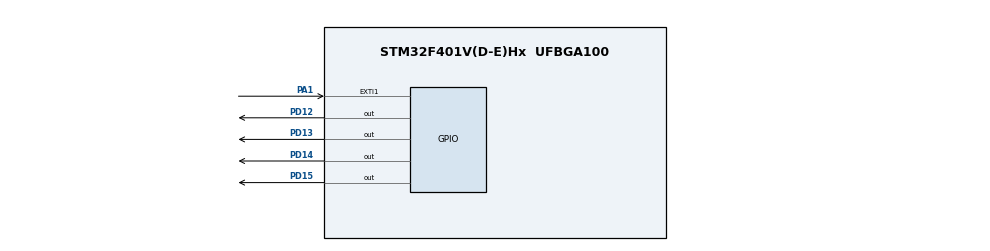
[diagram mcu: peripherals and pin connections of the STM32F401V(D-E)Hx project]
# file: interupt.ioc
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Mcu.Family=STM32F4
Mcu.Name=STM32F401V(D-E)Hx
Mcu.Package=UFBGA100
NVIC.EXTI1_IRQn=true\:0\:0\:false\:false\:true\:true\:true
NVIC.PriorityGroup=NVIC_PRIORITYGROUP_4
NVIC.TIM2_IRQn=true\:0\:0\:false\:false\:true\:true\:true
PA1.Signal=GPXTI1
PD12.GPIO_ModeDefaultOutputPP=GPIO_MODE_OUTPUT_PP
PD12.GPIO_PuPd=GPIO_NOPULL
PD12.GPIO_Speed=GPIO_SPEED_FREQ_HIGH
PD12.PinState=GPIO_PIN_RESET
PD12.Signal=GPIO_Output
PD13.GPIO_ModeDefaultOutputPP=GPIO_MODE_OUTPUT_PP
PD13.GPIO_PuPd=GPIO_NOPULL
PD13.GPIO_Speed=GPIO_SPEED_FREQ_HIGH
PD13.PinState=GPIO_PIN_RESET
PD13.Signal=GPIO_Output
PD14.GPIO_ModeDefaultOutputPP=GPIO_MODE_OUTPUT_PP
PD14.GPIO_PuPd=GPIO_NOPULL
PD14.GPIO_Speed=GPIO_SPEED_FREQ_HIGH
PD14.PinState=GPIO_PIN_RESET
PD14.Signal=GPIO_Output
PD15.GPIO_ModeDefaultOutputPP=GPIO_MODE_OUTPUT_PP
PD15.GPIO_PuPd=GPIO_NOPULL
PD15.GPIO_Speed=GPIO_SPEED_FREQ_HIGH
PD15.PinState=GPIO_PIN_RESET
PD15.Signal=GPIO_Output
PH0\ -\ OSC_IN.Mode=HSE-External-Oscillator
PH0\ -\ OSC_IN.Signal=RCC_OSC_IN
PH1\ -\ OSC_OUT.Mode=HSE-External-Oscillator
PH1\ -\ OSC_OUT.Signal=RCC_OSC_OUT
ProjectManager.HeapSize=0x200
ProjectManager.StackSize=0x400
ProjectManager.TargetToolchain=MDK-ARM V5.27
RCC.48MHZClocksFreq_Value=84000000
RCC.AHBFreq_Value=42000000
RCC.APB1Freq_Value=42000000
RCC.APB1TimFreq_Value=42000000
RCC.APB2Freq_Value=42000000
RCC.APB2TimFreq_Value=42000000
RCC.CortexFreq_Value=42000000
RCC.HCLKFreq_Value=42000000
RCC.HSE_VALUE=8000000
RCC.HSI_VALUE=16000000
RCC.LSE_VALUE=32768
RCC.PLLM=8
RCC.PLLN=336
RCC.PLLP=RCC_PLLP_DIV8
RCC.PLLSourceVirtual=RCC_PLLSOURCE_HSE
RCC.SYSCLKFreq_VALUE=42000000
RCC.SYSCLKSource=RCC_SYSCLKSOURCE_PLLCLK
RCC.VCOOutputFreq_Value=336000000
TIM2.AutoReloadPreload=TIM_AUTORELOAD_PRELOAD_ENABLE
TIM2.Period=499
TIM2.Prescaler=8000
VP_TIM2_VS_ClockSourceINT.Mode=Internal
board=custom

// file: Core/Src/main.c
/* USER CODE BEGIN Header */
/**
  ******************************************************************************
  * @file           : main.c
  * @brief          : Main program body
  ******************************************************************************
  * @attention
  *
  * <h2><center>&copy; Copyright (c) 2022 STMicroelectronics.
  * All rights reserved.</center></h2>
  *
  * This software component is licensed by ST under BSD 3-Clause license,
  * the "License"; You may not use this file except in compliance with the
  * License. You may obtain a copy of the License at:
  *                        opensource.org/licenses/BSD-3-Clause
  *
  ******************************************************************************
  */
/* USER CODE END Header */
#include "main.h"

TIM_HandleTypeDef htim2;

void SystemClock_Config(void);
static void MX_GPIO_Init(void);
static void MX_TIM2_Init(void);

int main(void)
{

  /* MCU Configuration--------------------------------------------------------*/

  /* Reset of all peripherals, Initializes the Flash interface and the Systick. */
  HAL_Init();

  /* Configure the system clock */
  SystemClock_Config();

  /* Initialize all configured peripherals */
  MX_GPIO_Init();
  MX_TIM2_Init();

  /* Infinite loop */
  while (1)
  {

  }
}

void SystemClock_Config(void)
{
  RCC_OscInitTypeDef RCC_OscInitStruct = {0};
  RCC_ClkInitTypeDef RCC_ClkInitStruct = {0};

  /** Configure the main internal regulator output voltage
  */
  __HAL_RCC_PWR_CLK_ENABLE();
  __HAL_PWR_VOLTAGESCALING_CONFIG(PWR_REGULATOR_VOLTAGE_SCALE2);
  /** Initializes the RCC Oscillators according to the specified parameters
  * in the RCC_OscInitTypeDef structure.
  */
  RCC_OscInitStruct.OscillatorType = RCC_OSCILLATORTYPE_HSI;
  RCC_OscInitStruct.HSIState = RCC_HSI_ON;
  RCC_OscInitStruct.HSICalibrationValue = RCC_HSICALIBRATION_DEFAULT;
  RCC_OscInitStruct.PLL.PLLState = RCC_PLL_NONE;
  if (HAL_RCC_OscConfig(&RCC_OscInitStruct) != HAL_OK)
  {
    Error_Handler();
  }
  /** Initializes the CPU, AHB and APB buses clocks
  */
  RCC_ClkInitStruct.ClockType = RCC_CLOCKTYPE_HCLK|RCC_CLOCKTYPE_SYSCLK
                              |RCC_CLOCKTYPE_PCLK1|RCC_CLOCKTYPE_PCLK2;
  RCC_ClkInitStruct.SYSCLKSource = RCC_SYSCLKSOURCE_HSI;
  RCC_ClkInitStruct.AHBCLKDivider = RCC_SYSCLK_DIV2;
  RCC_ClkInitStruct.APB1CLKDivider = RCC_HCLK_DIV1;
  RCC_ClkInitStruct.APB2CLKDivider = RCC_HCLK_DIV1;

  if (HAL_RCC_ClockConfig(&RCC_ClkInitStruct, FLASH_LATENCY_0) != HAL_OK)
  {
    Error_Handler();
  }
}

static void MX_TIM2_Init(void)
{

  TIM_ClockConfigTypeDef sClockSourceConfig = {0};
  TIM_MasterConfigTypeDef sMasterConfig = {0};

  htim2.Instance = TIM2;
  htim2.Init.Prescaler = 8000;
  htim2.Init.CounterMode = TIM_COUNTERMODE_UP;
  htim2.Init.Period = 499;
  htim2.Init.ClockDivision = TIM_CLOCKDIVISION_DIV1;
  htim2.Init.AutoReloadPreload = TIM_AUTORELOAD_PRELOAD_ENABLE;
  if (HAL_TIM_Base_Init(&htim2) != HAL_OK)
  {
    Error_Handler();
  }
  sClockSourceConfig.ClockSource = TIM_CLOCKSOURCE_INTERNAL;
  if (HAL_TIM_ConfigClockSource(&htim2, &sClockSourceConfig) != HAL_OK)
  {
    Error_Handler();
  }
  sMasterConfig.MasterOutputTrigger = TIM_TRGO_RESET;
  sMasterConfig.MasterSlaveMode = TIM_MASTERSLAVEMODE_DISABLE;
  if (HAL_TIMEx_MasterConfigSynchronization(&htim2, &sMasterConfig) != HAL_OK)
  {
    Error_Handler();
  }

}

static void MX_GPIO_Init(void)
{
  GPIO_InitTypeDef GPIO_InitStruct = {0};

  /* GPIO Ports Clock Enable */
  __HAL_RCC_GPIOH_CLK_ENABLE();
  __HAL_RCC_GPIOD_CLK_ENABLE();
  __HAL_RCC_GPIOA_CLK_ENABLE();

  /*Configure GPIO pin Output Level */
  HAL_GPIO_WritePin(GPIOD, GPIO_PIN_15|GPIO_PIN_14|GPIO_PIN_13|GPIO_PIN_12, GPIO_PIN_RESET);

  /*Configure GPIO pins : PD15 PD14 PD13 PD12 */
  GPIO_InitStruct.Pin = GPIO_PIN_15|GPIO_PIN_14|GPIO_PIN_13|GPIO_PIN_12;
  GPIO_InitStruct.Mode = GPIO_MODE_OUTPUT_PP;
  GPIO_InitStruct.Pull = GPIO_NOPULL;
  GPIO_InitStruct.Speed = GPIO_SPEED_FREQ_HIGH;
  HAL_GPIO_Init(GPIOD, &GPIO_InitStruct);

  /*Configure GPIO pin : PA1 */
  GPIO_InitStruct.Pin = GPIO_PIN_1;
  GPIO_InitStruct.Mode = GPIO_MODE_IT_RISING;
  GPIO_InitStruct.Pull = GPIO_NOPULL;
  HAL_GPIO_Init(GPIOA, &GPIO_InitStruct);

  /* EXTI interrupt init*/
  HAL_NVIC_SetPriority(EXTI1_IRQn, 0, 0);
  HAL_NVIC_EnableIRQ(EXTI1_IRQn);

}

void Error_Handler(void)
{
  __disable_irq();
  while (1)
  {
  }
}

/************************ (C) COPYRIGHT STMicroelectronics *****END OF FILE****/
